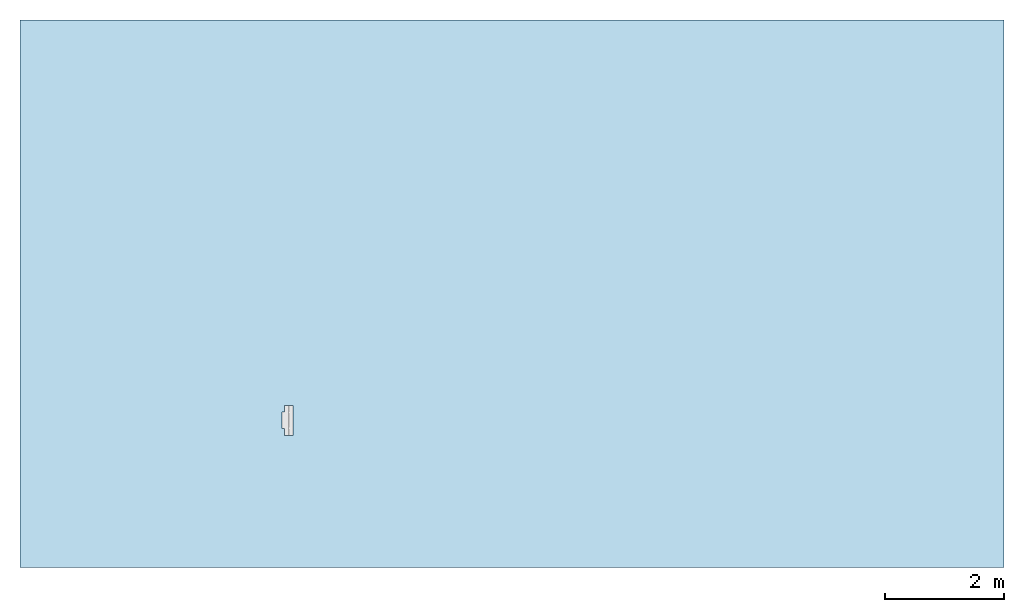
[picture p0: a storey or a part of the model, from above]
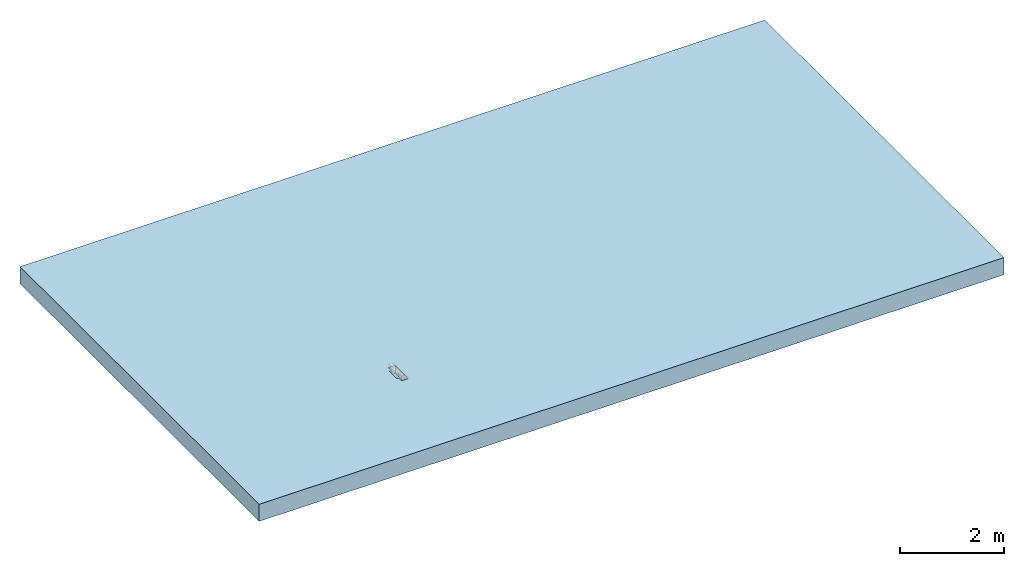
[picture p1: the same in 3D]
Properties of the parts of a building model (IFC2X3)

# File
Description: ViewDefinition [CoordinationView]
File name: 7937 - Access Unit - 500mm LG.ifc
Time: 2013-09-02T12:31:27
Written by: Autodesk Revit 2013
Made in: 20120221_2030(x64)

# IfcProject, Project Number
LongName: Project Name; Phase: Project Status

# IfcSite, Default
RefLatitude: 42, 21, 30, 344238; RefLongitude: -71, -3, -35, -194702; RefElevation: 0 mm

# IfcBuilding
Pset_BuildingCommon - NumberOfStoreys: 1
Other - Project Number: Project Number; Project Issue Date: Issue Date; Project Status: Project Status; Project Address: ## Street City, State Zip; Project Name: Project Name; Client Name: Owner

# IfcBuildingStorey, Level 1
LongName: Level 1; Elevation: 0 mm
Constraints - Elevation Base: 0; Elevation: 0 mm
Graphics - Line Pattern: Center; Color: 0; Line Weight: 1; Symbol at End 2 Default: yes; Symbol at End 1 Default: no; Symbol: M_Level Head - Circle: M_Level Head - Circle
Identity Data - Name: Level 1; Structural: no; Building Story: yes
Dimensions - Computation Height: 0 mm

# IfcBuildingElementProxy: 7937 - Access Unit - 500mm LG, Civil-Drainage-Channel-ACO-KerbDrain-SP280:7937 - Access Unit - 500mm LG:7937 - Access Unit - 500mm LG:311063
In: Level 1
Material: ACO Polymer Concrete., Iron, Cast
Other - Revision: 1; CreatedBy: www.aco.co.uk
Constraints - Moves With Nearby Elements: no; Level: Level: Level 1
Phasing - Phase Created: New Construction
Dimensions - Volume: 15085570 mm3; Void Width: 150 mm; Endcap void: 230 mm; Void Depth: -180 mm; Access hole: -41.54 mm; AccessDepth: 26 mm; Void Length: 500 mm
Pset_BuildingElementProxyCommon - Reference: 7937 - Access Unit - 500mm LG
Green Building Properties - Channel Recycled Material Content: 20% minimum; End Cap Recyclable: N/A; Channel Recyclable: Fully recyclable; Access Cover/Frame Recycled Material Content: Between 40% - 90%; End Cap Recycled Material Content: N/A; Access Cover/Frame Recyclable: Fully recyclable
Materials and Finishes - End Cap Colour: N/A; Channel Material: Vienite® Synthetic Resin Concrete; Access Cover/Frame Material: Ductile Iron; Connection Pipe Material Colour: N/A; Channel Colour: Grey; Access Cover/Frame Colour: Black; Access Cover/Frame Finish: Water Based Paint Coating; Connection Pipe Material: N/A; End Cap Material: N/A
Identity Data - URL: www.aco.co.uk; Telephone: +44 (0)1462 816666; Assembly Description: Rain Water Drainage; Installation guidelines: http://www.aco.co.uk/download.php?id=120; Model: ACO KerbDrain SP280; Price: POA - contact ACO; Model Description: Combined kerb and drainage system; Assembly Code: D2040; e-mail Technical: technical@aco.co.uk; Type Comments: ACO KerbDrain SP280 splayed access unit 500mm long; Cost: 0; Fax: +44 (0)1462 815895; Product Page URL: http://www.aco.co.uk/product_detail.php?id=3; e-mail Sales: customersupport@aco.co.uk; OmniClass Title: Rainwater Removal; Maintenance guidelines: http://www.aco.co.uk/download.php?id=120; Product Code: 7937; Product brochure: http://www.aco.co.uk/download.php?id=120; Manufacturer: ACO Technologies plc - ACO Water Management Division; Address: ACO Business Park, Hitchin Road, Shefford, Bedfordshire, United Kingdom SG17 5TE; OmniClass Number: 23.70.50.24
Data - ACO Hydraulic Design Software: http://www.acodesign.co.uk; Concrete Surround Volume - Load Class A 15 - D 400 - Concrete Pavement: 0.14m³/m; Invert Depth: 255mm; Load Class: A 15 - D 400; Product Weight: 36.1 Kg; Concrete Surround Volume - Load Class A 15 - D 400 - Grass or Asphalt Pavement: 0.12m³/m; Product Dimensions: 500mm x 150mm x 280mm (LxWxH); Drainage Slot Intake area: N/A; Installation - Concrete Grade: Refer to brochure; Connection Pipe O.D: N/A; Hydraulic Performance: http://www.aco.co.uk/download.php?id=120; Product Standard: BS EN 1433:2002, CE marked, Kitemarked; Channel C.S.A: 0.02m²; Drainage Slot Width: N/A
Construction - Access Unit: yes; Closing end cap: no; SP280 - 1000: no; LH drop kerb: no; RH inlet/outlet end cap: no; perforated centre stone: no; RH drop kerb: no; SP280-500: no; LH transition unit: no; Centre Stone: no; LH inlet/outlet end cap: no; RH transition unit: no
General - SerialNumber: 0.000000; TagNumber: 0.000000

# IfcOpeningElement: Recess
In: Level 1
Dimensions - Area: 151470000 mm2; Volume: 60572403758 mm3; Thickness: 400 mm; Perimeter: 51360 mm
Phasing - Phase Created: New Construction
Structural - Structural: no; Enable Analytical Model: no
Constraints - Related to Mass: no; Room Bounding: yes; Height Offset From Level: 0 mm; Level: Level: Level 1
Graphics - Coarse Scale Fill Color: 0
Analytical Properties - Roughness: 1; Absorptance: 0.1
Construction - Function: 0; Default Thickness: 400 mm
Materials and Finishes - Structural Material: Plant

# IfcSlab: Floor:Generic Floor - 400mm, Floor:Generic Floor - 400mm:193825
In: Level 1
PredefinedType: FLOOR; Material: Plant 400 mm
Dimensions - Area: 151470000 mm2; Volume: 60572403758 mm3; Thickness: 400 mm; Perimeter: 51360 mm
Phasing - Phase Created: New Construction
Structural - Structural: no; Enable Analytical Model: no
Constraints - Related to Mass: no; Room Bounding: yes; Height Offset From Level: 0 mm; Level: Level: Level 1
Pset_SlabCommon - Reference: Generic Floor - 400mm; IsExternal: no; LoadBearing: yes
Graphics - Coarse Scale Fill Color: 0
Analytical Properties - Roughness: 1; Absorptance: 0.1
Construction - Function: 0; Default Thickness: 400 mm
Materials and Finishes - Structural Material: Plant
